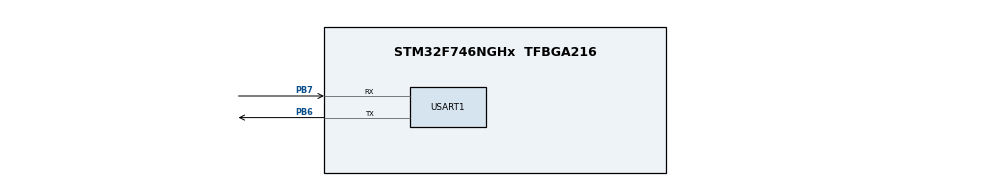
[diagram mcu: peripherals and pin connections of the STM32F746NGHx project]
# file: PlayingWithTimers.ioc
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Mcu.Family=STM32F7
Mcu.Name=STM32F746NGHx
Mcu.Package=TFBGA216
NVIC.PriorityGroup=NVIC_PRIORITYGROUP_4
PB6.Mode=Asynchronous
PB6.Signal=USART1_TX
PB7.Mode=Asynchronous
PB7.Signal=USART1_RX
PH0/OSC_IN.Mode=HSE-External-Oscillator
PH0/OSC_IN.Signal=RCC_OSC_IN
PH1/OSC_OUT.Mode=HSE-External-Oscillator
PH1/OSC_OUT.Signal=RCC_OSC_OUT
ProjectManager.HeapSize=0x200
ProjectManager.StackSize=0x400
ProjectManager.TargetToolchain=STM32CubeIDE
RCC.AHBFreq_Value=192000000
RCC.APB1CLKDivider=RCC_HCLK_DIV4
RCC.APB1Freq_Value=48000000
RCC.APB1TimFreq_Value=96000000
RCC.APB2CLKDivider=RCC_HCLK_DIV2
RCC.APB2Freq_Value=96000000
RCC.APB2TimFreq_Value=192000000
RCC.CortexFreq_Value=192000000
RCC.HCLKFreq_Value=192000000
RCC.HSE_VALUE=25000000
RCC.HSI_VALUE=16000000
RCC.LSE_VALUE=32768
RCC.PLLM=8
RCC.SYSCLKFreq_VALUE=192000000
RCC.SYSCLKSource=RCC_SYSCLKSOURCE_PLLCLK
RCC.USBFreq_Value=192000000
RCC.VCOOutputFreq_Value=384000000
TIM2.Period=1000-1
TIM2.Prescaler=10800-1
USART1.VirtualMode-Asynchronous=VM_ASYNC
VP_TIM2_VS_ClockSourceINT.Mode=Internal
board=custom

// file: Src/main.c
/* USER CODE BEGIN Header */
/**
  ******************************************************************************
  * @file           : main.c
  * @brief          : Main program body
  ******************************************************************************
  * @attention
  *
  * <h2><center>&copy; Copyright (c) 2019 STMicroelectronics.
  * All rights reserved.</center></h2>
  *
  * This software component is licensed by ST under BSD 3-Clause license,
  * the "License"; You may not use this file except in compliance with the
  * License. You may obtain a copy of the License at:
  *                        opensource.org/licenses/BSD-3-Clause
  *
  ******************************************************************************
  */
/* USER CODE END Header */

#include "main.h"

/* USER CODE BEGIN Includes */
#include "string.h"
#include "stm32746g_discovery.h"

/* USER CODE END Includes */

TIM_HandleTypeDef htim2;

UART_HandleTypeDef huart1;

void SystemClock_Config(void);
static void MX_GPIO_Init(void);
static void MX_USART1_UART_Init(void);
static void MX_TIM2_Init(void);

int main(void)
{

  /* MCU Configuration--------------------------------------------------------*/

  /* Reset of all peripherals, Initializes the Flash interface and the Systick. */
  HAL_Init();

  /* Configure the system clock */
  SystemClock_Config();

  /* USER CODE BEGIN SysInit */
  BSP_LED_Init(LED_GREEN);

  /* USER CODE END SysInit */

  /* Initialize all configured peripherals */
  MX_GPIO_Init();
  MX_USART1_UART_Init();
  MX_TIM2_Init();
  /* USER CODE BEGIN 2 */

  char hello[] = "Hello World!\r\n";
  /* USER CODE END 2 */

  /* Infinite loop */
  while (1)
  {

    /* USER CODE BEGIN 3 */
	  HAL_Delay(1000);

	  HAL_UART_Transmit(&huart1, (uint8_t*) hello, strlen(hello), 0xFFFF);
  }
  /* USER CODE END 3 */
}

void SystemClock_Config(void)
{
  RCC_OscInitTypeDef RCC_OscInitStruct = {0};
  RCC_ClkInitTypeDef RCC_ClkInitStruct = {0};
  RCC_PeriphCLKInitTypeDef PeriphClkInitStruct = {0};

  /** Configure the main internal regulator output voltage
  */
  __HAL_RCC_PWR_CLK_ENABLE();
  __HAL_PWR_VOLTAGESCALING_CONFIG(PWR_REGULATOR_VOLTAGE_SCALE1);
  /** Initializes the CPU, AHB and APB busses clocks
  */
  RCC_OscInitStruct.OscillatorType = RCC_OSCILLATORTYPE_HSI;
  RCC_OscInitStruct.HSIState = RCC_HSI_ON;
  RCC_OscInitStruct.HSICalibrationValue = RCC_HSICALIBRATION_DEFAULT;
  RCC_OscInitStruct.PLL.PLLState = RCC_PLL_ON;
  RCC_OscInitStruct.PLL.PLLSource = RCC_PLLSOURCE_HSI;
  RCC_OscInitStruct.PLL.PLLM = 8;
  RCC_OscInitStruct.PLL.PLLN = 216;
  RCC_OscInitStruct.PLL.PLLP = RCC_PLLP_DIV2;
  RCC_OscInitStruct.PLL.PLLQ = 2;
  if (HAL_RCC_OscConfig(&RCC_OscInitStruct) != HAL_OK)
  {
    Error_Handler();
  }
  /** Activate the Over-Drive mode
  */
  if (HAL_PWREx_EnableOverDrive() != HAL_OK)
  {
    Error_Handler();
  }
  /** Initializes the CPU, AHB and APB busses clocks
  */
  RCC_ClkInitStruct.ClockType = RCC_CLOCKTYPE_HCLK|RCC_CLOCKTYPE_SYSCLK
                              |RCC_CLOCKTYPE_PCLK1|RCC_CLOCKTYPE_PCLK2;
  RCC_ClkInitStruct.SYSCLKSource = RCC_SYSCLKSOURCE_PLLCLK;
  RCC_ClkInitStruct.AHBCLKDivider = RCC_SYSCLK_DIV1;
  RCC_ClkInitStruct.APB1CLKDivider = RCC_HCLK_DIV4;
  RCC_ClkInitStruct.APB2CLKDivider = RCC_HCLK_DIV2;

  if (HAL_RCC_ClockConfig(&RCC_ClkInitStruct, FLASH_LATENCY_6) != HAL_OK)
  {
    Error_Handler();
  }
  PeriphClkInitStruct.PeriphClockSelection = RCC_PERIPHCLK_USART1;
  PeriphClkInitStruct.Usart1ClockSelection = RCC_USART1CLKSOURCE_PCLK2;
  if (HAL_RCCEx_PeriphCLKConfig(&PeriphClkInitStruct) != HAL_OK)
  {
    Error_Handler();
  }
}

static void MX_TIM2_Init(void)
{

  TIM_ClockConfigTypeDef sClockSourceConfig = {0};
  TIM_MasterConfigTypeDef sMasterConfig = {0};

  htim2.Instance = TIM2;
  htim2.Init.Prescaler = 10800-1;
  htim2.Init.CounterMode = TIM_COUNTERMODE_UP;
  htim2.Init.Period = 1000-1;
  htim2.Init.ClockDivision = TIM_CLOCKDIVISION_DIV1;
  htim2.Init.AutoReloadPreload = TIM_AUTORELOAD_PRELOAD_DISABLE;
  if (HAL_TIM_Base_Init(&htim2) != HAL_OK)
  {
    Error_Handler();
  }
  sClockSourceConfig.ClockSource = TIM_CLOCKSOURCE_INTERNAL;
  if (HAL_TIM_ConfigClockSource(&htim2, &sClockSourceConfig) != HAL_OK)
  {
    Error_Handler();
  }
  sMasterConfig.MasterOutputTrigger = TIM_TRGO_RESET;
  sMasterConfig.MasterSlaveMode = TIM_MASTERSLAVEMODE_DISABLE;
  if (HAL_TIMEx_MasterConfigSynchronization(&htim2, &sMasterConfig) != HAL_OK)
  {
    Error_Handler();
  }

}

static void MX_USART1_UART_Init(void)
{

  huart1.Instance = USART1;
  huart1.Init.BaudRate = 115200;
  huart1.Init.WordLength = UART_WORDLENGTH_8B;
  huart1.Init.StopBits = UART_STOPBITS_1;
  huart1.Init.Parity = UART_PARITY_NONE;
  huart1.Init.Mode = UART_MODE_TX_RX;
  huart1.Init.HwFlowCtl = UART_HWCONTROL_NONE;
  huart1.Init.OverSampling = UART_OVERSAMPLING_16;
  huart1.Init.OneBitSampling = UART_ONE_BIT_SAMPLE_DISABLE;
  huart1.AdvancedInit.AdvFeatureInit = UART_ADVFEATURE_NO_INIT;
  if (HAL_UART_Init(&huart1) != HAL_OK)
  {
    Error_Handler();
  }

}

static void MX_GPIO_Init(void)
{

  /* GPIO Ports Clock Enable */
  __HAL_RCC_GPIOB_CLK_ENABLE();
  __HAL_RCC_GPIOH_CLK_ENABLE();

}

void Error_Handler(void)
{
}

/************************ (C) COPYRIGHT STMicroelectronics *****END OF FILE****/
